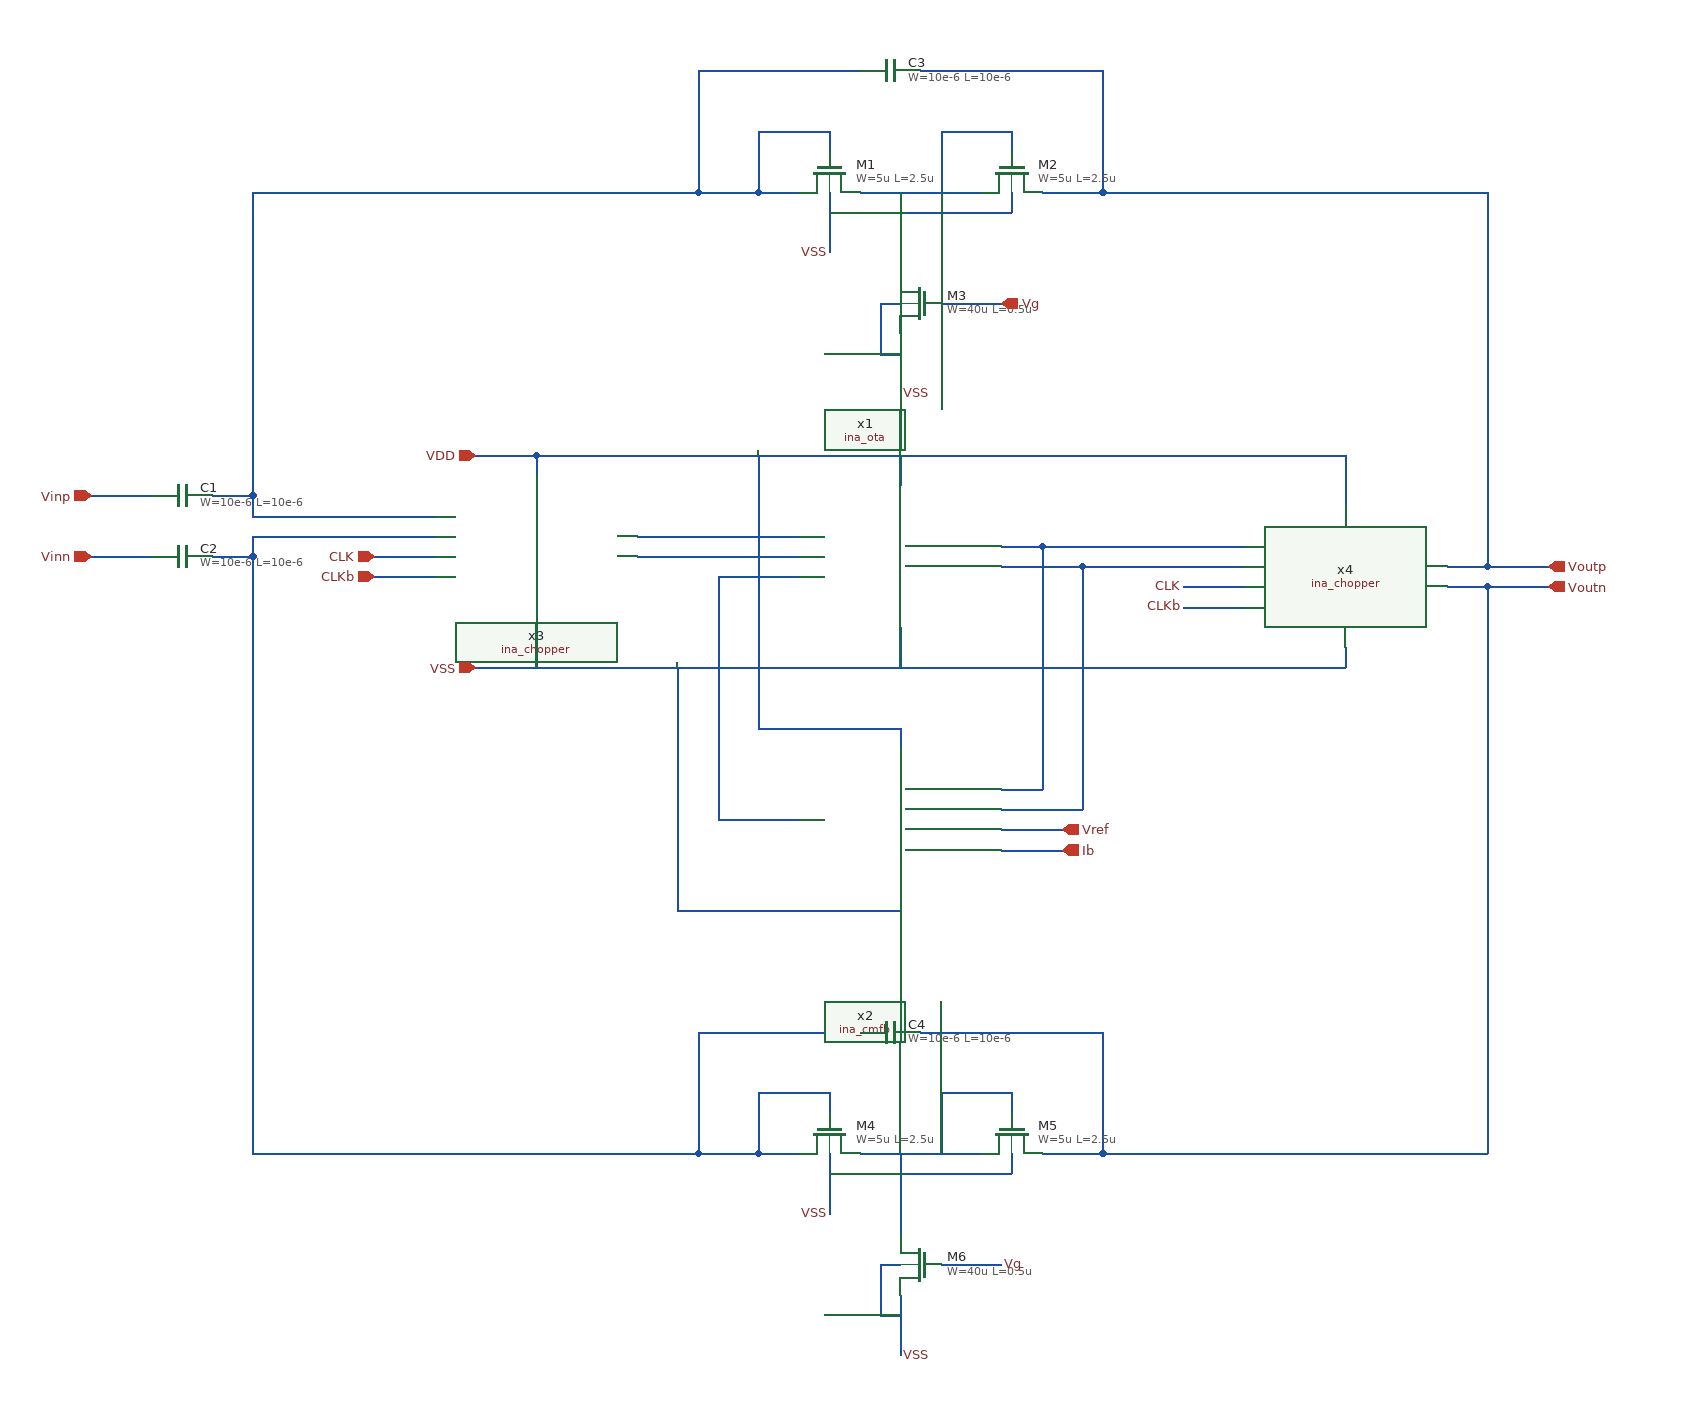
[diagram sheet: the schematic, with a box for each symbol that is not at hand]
v {xschem version=3.4.7 file_version=1.2}
G {}
K {}
V {}
S {}
E {}
N 1980 -1430 2040 -1430 {lab=CLK}
N 1980 -1410 2040 -1410 {lab=CLKb}
N 1440 -1480 1600 -1480 {lab=#net1}
N 1440 -1460 1600 -1460 {lab=#net2}
N 1630 -1880 1630 -1860 {lab=#net3}
N 1720 -1820 1780 -1820 {lab=#net4}
N 1810 -1880 1810 -1860 {lab=#net4}
N 1660 -1820 1720 -1820 {lab=#net4}
N 1740 -1880 1740 -1820 {lab=#net4}
N 1740 -1880 1810 -1880 {lab=#net4}
N 1560 -1820 1600 -1820 {lab=#net3}
N 1560 -1880 1560 -1820 {lab=#net3}
N 1560 -1880 1630 -1880 {lab=#net3}
N 1700 -1820 1700 -1740 {lab=#net4}
N 1700 -1680 1700 -1620 {lab=VSS}
N 1680 -1710 1700 -1710 {lab=VSS}
N 1680 -1710 1680 -1660 {lab=VSS}
N 1680 -1660 1700 -1660 {lab=VSS}
N 1630 -1820 1630 -1760 {lab=VSS}
N 1630 -1800 1810 -1800 {lab=VSS}
N 1810 -1820 1810 -1800 {lab=VSS}
N 1500 -1820 1560 -1820 {lab=#net3}
N 1500 -1940 1500 -1820 {lab=#net3}
N 1500 -1940 1660 -1940 {lab=#net3}
N 1840 -1820 1900 -1820 {lab=Voutp}
N 1900 -1940 1900 -1820 {lab=Voutp}
N 1720 -1940 1900 -1940 {lab=Voutp}
N 1180 -1460 1240 -1460 {lab=CLK}
N 1180 -1440 1240 -1440 {lab=CLKb}
N 1020 -1460 1060 -1460 {lab=#net5}
N 1060 -1480 1060 -1460 {lab=#net5}
N 1020 -1520 1060 -1520 {lab=#net3}
N 1060 -1520 1060 -1500 {lab=#net3}
N 1060 -1500 1240 -1500 {lab=#net3}
N 1060 -1480 1240 -1480 {lab=#net5}
N 900 -1520 960 -1520 {lab=Vinp}
N 900 -1460 960 -1460 {lab=Vinn}
N 1340 -1560 1340 -1540 {lab=VDD}
N 2140 -1560 2140 -1510 {lab=VDD}
N 1700 -1560 1700 -1530 {lab=VDD}
N 1280 -1560 1340 -1560 {lab=VDD}
N 2140 -1370 2140 -1350 {lab=VSS}
N 1700 -1390 1700 -1350 {lab=VSS}
N 1340 -1400 1340 -1350 {lab=VSS}
N 1700 -1290 1700 -1270 {lab=VDD}
N 1560 -1290 1700 -1290 {lab=VDD}
N 1560 -1560 1560 -1290 {lab=VDD}
N 1520 -1200 1600 -1200 {lab=#net6}
N 1520 -1440 1520 -1200 {lab=#net6}
N 1520 -1440 1600 -1440 {lab=#net6}
N 1280 -1350 2140 -1350 {lab=VSS}
N 1800 -1230 1840 -1230 {lab=#net7}
N 1840 -1470 1840 -1230 {lab=#net7}
N 1800 -1210 1880 -1210 {lab=#net8}
N 1880 -1450 1880 -1210 {lab=#net8}
N 1340 -1560 2140 -1560 {lab=VDD}
N 1700 -1130 1700 -1110 {lab=VSS}
N 1480 -1110 1700 -1110 {lab=VSS}
N 1480 -1350 1480 -1110 {lab=VSS}
N 1800 -1190 1860 -1190 {lab=Vref}
N 1800 -1170 1860 -1170 {lab=Ib}
N 2240 -1450 2280 -1450 {lab=Voutp}
N 2280 -1820 2280 -1450 {lab=Voutp}
N 1900 -1820 2280 -1820 {lab=Voutp}
N 1060 -1820 1500 -1820 {lab=#net3}
N 1060 -1820 1060 -1520 {lab=#net3}
N 1630 -930 1630 -910 {lab=#net5}
N 1720 -870 1780 -870 {lab=#net9}
N 1810 -930 1810 -910 {lab=#net9}
N 1660 -870 1720 -870 {lab=#net9}
N 1740 -930 1740 -870 {lab=#net9}
N 1740 -930 1810 -930 {lab=#net9}
N 1560 -870 1600 -870 {lab=#net5}
N 1560 -930 1560 -870 {lab=#net5}
N 1560 -930 1630 -930 {lab=#net5}
N 1740 -760 1800 -760 {lab=Vg}
N 1700 -870 1700 -790 {lab=#net9}
N 1700 -730 1700 -670 {lab=VSS}
N 1680 -760 1700 -760 {lab=VSS}
N 1680 -760 1680 -710 {lab=VSS}
N 1680 -710 1700 -710 {lab=VSS}
N 1630 -870 1630 -810 {lab=VSS}
N 1630 -850 1810 -850 {lab=VSS}
N 1810 -870 1810 -850 {lab=VSS}
N 1500 -870 1560 -870 {lab=#net5}
N 1500 -990 1500 -870 {lab=#net5}
N 1500 -990 1660 -990 {lab=#net5}
N 1840 -870 1900 -870 {lab=Voutn}
N 1900 -990 1900 -870 {lab=Voutn}
N 1720 -990 1900 -990 {lab=Voutn}
N 1900 -870 2280 -870 {lab=Voutn}
N 2280 -1430 2280 -870 {lab=Voutn}
N 2240 -1430 2280 -1430 {lab=Voutn}
N 1060 -870 1500 -870 {lab=#net5}
N 1060 -1460 1060 -870 {lab=#net5}
N 1740 -1710 1800 -1710 {lab=Vg}
N 2280 -1450 2340 -1450 {lab=Voutp}
N 2280 -1430 2340 -1430 {lab=Voutn}
N 1800 -1470 1840 -1470 {lab=#net7}
N 1800 -1450 1880 -1450 {lab=#net8}
N 1880 -1450 2040 -1450 {lab=#net8}
N 1840 -1470 2040 -1470 {lab=#net7}
C {title-2.sym} 0 0 0 0 {name=l1 author="Julio Vilca" rev=1.0 lock=true}
C {libs/core_ina/ina_ota/ina_ota.sym} 1700 -1460 0 0 {name=x1}
C {libs/core_ina/ina_cmfb/ina_cmfb.sym} 1700 -1200 0 1 {name=x2}
C {libs/core_ina/ina_chopper/ina_chopper.sym} 1340 -1470 0 0 {name=x3}
C {libs/core_ina/ina_chopper/ina_chopper.sym} 2140 -1440 0 0 {name=x4}
C {lab_wire.sym} 1980 -1430 0 0 {name=p1 sig_type=std_logic lab=CLK}
C {lab_wire.sym} 1980 -1410 0 0 {name=p2 sig_type=std_logic lab=CLKb}
C {symbols/nfet_03v3.sym} 1630 -1840 3 1 {name=M1
L=2.5u
W=5u
nf=1
m=1
ad="'int((nf+1)/2) * W/nf * 0.18u'"
pd="'2*int((nf+1)/2) * (W/nf + 0.18u)'"
as="'int((nf+2)/2) * W/nf * 0.18u'"
ps="'2*int((nf+2)/2) * (W/nf + 0.18u)'"
nrd="'0.18u / W'" nrs="'0.18u / W'"
sa=0 sb=0 sd=0
model=nfet_03v3
spiceprefix=X
}
C {symbols/nfet_03v3.sym} 1810 -1840 3 1 {name=M2
L=2.5u
W=5u
nf=1
m=1
ad="'int((nf+1)/2) * W/nf * 0.18u'"
pd="'2*int((nf+1)/2) * (W/nf + 0.18u)'"
as="'int((nf+2)/2) * W/nf * 0.18u'"
ps="'2*int((nf+2)/2) * (W/nf + 0.18u)'"
nrd="'0.18u / W'" nrs="'0.18u / W'"
sa=0 sb=0 sd=0
model=nfet_03v3
spiceprefix=X
}
C {symbols/nfet_03v3.sym} 1720 -1710 0 1 {name=M3
L=0.5u
W=40u
nf=1
m=4
ad="'int((nf+1)/2) * W/nf * 0.18u'"
pd="'2*int((nf+1)/2) * (W/nf + 0.18u)'"
as="'int((nf+2)/2) * W/nf * 0.18u'"
ps="'2*int((nf+2)/2) * (W/nf + 0.18u)'"
nrd="'0.18u / W'" nrs="'0.18u / W'"
sa=0 sb=0 sd=0
model=nfet_03v3
spiceprefix=X
}
C {symbols/cap_mim_2f0fF.sym} 990 -1520 3 0 {name=C1
W=10e-6
L=10e-6
model=cap_mim_2f0fF
spiceprefix=X
m=10}
C {symbols/cap_mim_2f0fF.sym} 990 -1460 3 1 {name=C2
W=10e-6
L=10e-6
model=cap_mim_2f0fF
spiceprefix=X
m=10}
C {symbols/cap_mim_2f0fF.sym} 1690 -1940 3 0 {name=C3
W=10e-6
L=10e-6
model=cap_mim_2f0fF
spiceprefix=X
m=1}
C {lab_wire.sym} 1700 -1620 2 0 {name=p4 sig_type=std_logic lab=VSS}
C {lab_wire.sym} 1630 -1760 3 0 {name=p5 sig_type=std_logic lab=VSS}
C {ipin.sym} 1180 -1460 0 0 {name=p7 lab=CLK}
C {ipin.sym} 1180 -1440 0 0 {name=p8 lab=CLKb}
C {ipin.sym} 900 -1520 0 0 {name=p9 lab=Vinp}
C {ipin.sym} 900 -1460 0 0 {name=p10 lab=Vinn}
C {ipin.sym} 1280 -1560 0 0 {name=p11 lab=VDD}
C {ipin.sym} 1280 -1350 0 0 {name=p12 lab=VSS}
C {ipin.sym} 1860 -1190 0 1 {name=p6 lab=Vref}
C {ipin.sym} 1860 -1170 0 1 {name=p13 lab=Ib}
C {symbols/nfet_03v3.sym} 1630 -890 3 1 {name=M4
L=2.5u
W=5u
nf=1
m=1
ad="'int((nf+1)/2) * W/nf * 0.18u'"
pd="'2*int((nf+1)/2) * (W/nf + 0.18u)'"
as="'int((nf+2)/2) * W/nf * 0.18u'"
ps="'2*int((nf+2)/2) * (W/nf + 0.18u)'"
nrd="'0.18u / W'" nrs="'0.18u / W'"
sa=0 sb=0 sd=0
model=nfet_03v3
spiceprefix=X
}
C {symbols/nfet_03v3.sym} 1810 -890 3 1 {name=M5
L=2.5u
W=5u
nf=1
m=1
ad="'int((nf+1)/2) * W/nf * 0.18u'"
pd="'2*int((nf+1)/2) * (W/nf + 0.18u)'"
as="'int((nf+2)/2) * W/nf * 0.18u'"
ps="'2*int((nf+2)/2) * (W/nf + 0.18u)'"
nrd="'0.18u / W'" nrs="'0.18u / W'"
sa=0 sb=0 sd=0
model=nfet_03v3
spiceprefix=X
}
C {symbols/nfet_03v3.sym} 1720 -760 0 1 {name=M6
L=0.5u
W=40u
nf=1
m=4
ad="'int((nf+1)/2) * W/nf * 0.18u'"
pd="'2*int((nf+1)/2) * (W/nf + 0.18u)'"
as="'int((nf+2)/2) * W/nf * 0.18u'"
ps="'2*int((nf+2)/2) * (W/nf + 0.18u)'"
nrd="'0.18u / W'" nrs="'0.18u / W'"
sa=0 sb=0 sd=0
model=nfet_03v3
spiceprefix=X
}
C {symbols/cap_mim_2f0fF.sym} 1690 -990 3 0 {name=C4
W=10e-6
L=10e-6
model=cap_mim_2f0fF
spiceprefix=X
m=1}
C {lab_wire.sym} 1800 -760 0 1 {name=p14 sig_type=std_logic lab=Vg}
C {lab_wire.sym} 1700 -670 2 0 {name=p15 sig_type=std_logic lab=VSS}
C {lab_wire.sym} 1630 -810 3 0 {name=p16 sig_type=std_logic lab=VSS}
C {ipin.sym} 1800 -1710 0 1 {name=p3 lab=Vg}
C {opin.sym} 2340 -1450 0 0 {name=p17 lab=Voutp}
C {opin.sym} 2340 -1430 0 0 {name=p18 lab=Voutn}
